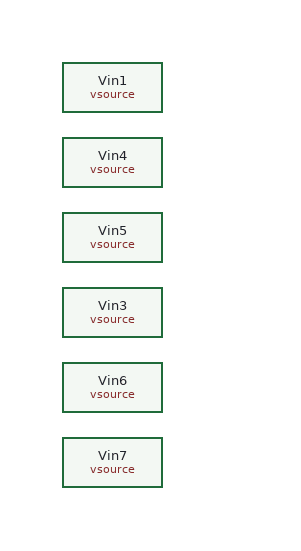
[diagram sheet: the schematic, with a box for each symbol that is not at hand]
v {xschem version=3.4.6 file_version=1.2}
G {}
K {}
V {}
S {}
E {}
C {devices/vsource.sym} -10 -75 0 1 {name=Vin1 value=0.8
spice_ignore=false}
C {devices/vsource.sym} -10 -15 0 1 {name=Vin4 value="SINE(0 -0.3821 1000 0 0)"
spice_ignore=false}
C {devices/vsource.sym} -10 45 0 1 {name=Vin5 value="SINE(0 -0.1273 3000 0 0)"
spice_ignore=false}
C {devices/vsource.sym} -10 105 0 1 {name=Vin3 value="SINE(0 -0.0763 5000 0 0)"
spice_ignore=false}
C {devices/vsource.sym} -10 165 0 1 {name=Vin6 value="SINE(0 -0.0545 7000 0 0)"
spice_ignore=false}
C {devices/vsource.sym} -10 225 0 1 {name=Vin7 value="SINE(0 -0.0413 9000 0 0)"
spice_ignore=false}
